VERSION 5.7 ;
  NAMESCASESENSITIVE ON ;
  NOWIREEXTENSIONATPIN ON ;
  DIVIDERCHAR "/" ;
  BUSBITCHARS "[]" ;
UNITS
  DATABASE MICRONS 200 ;
END UNITS

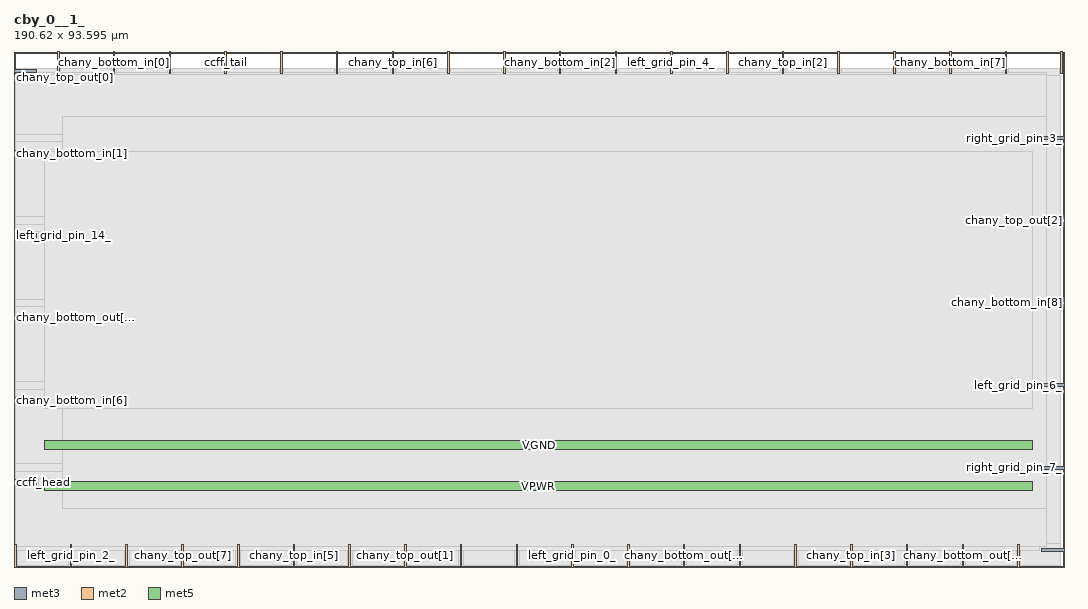
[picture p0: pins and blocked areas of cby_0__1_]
MACRO cby_0__1_
  CLASS BLOCK ;
  FOREIGN cby_0__1_ ;
  ORIGIN 0.000 0.000 ;
  SIZE 190.620 BY 93.595 ;
  PIN ccff_head
    DIRECTION INPUT ;
    PORT
      LAYER met3 ;
        RECT 0.000 15.000 4.000 15.600 ;
    END
  END ccff_head
  PIN ccff_tail
    DIRECTION OUTPUT TRISTATE ;
    PORT
      LAYER met2 ;
        RECT 38.270 89.595 38.550 93.595 ;
    END
  END ccff_tail
  PIN chany_bottom_in[0]
    DIRECTION INPUT ;
    PORT
      LAYER met2 ;
        RECT 18.030 89.595 18.310 93.595 ;
    END
  END chany_bottom_in[0]
  PIN chany_bottom_in[1]
    DIRECTION INPUT ;
    PORT
      LAYER met3 ;
        RECT 0.000 74.840 4.000 75.440 ;
    END
  END chany_bottom_in[1]
  PIN chany_bottom_in[2]
    DIRECTION INPUT ;
    PORT
      LAYER met2 ;
        RECT 98.990 89.595 99.270 93.595 ;
    END
  END chany_bottom_in[2]
  PIN chany_bottom_in[3]
    DIRECTION INPUT ;
    PORT
      LAYER met2 ;
        RECT 91.170 0.000 91.450 4.000 ;
    END
  END chany_bottom_in[3]
  PIN chany_bottom_in[4]
    DIRECTION INPUT ;
    PORT
      LAYER met2 ;
        RECT 111.410 0.000 111.690 4.000 ;
    END
  END chany_bottom_in[4]
  PIN chany_bottom_in[5]
    DIRECTION INPUT ;
    PORT
      LAYER met2 ;
        RECT 78.750 89.595 79.030 93.595 ;
    END
  END chany_bottom_in[5]
  PIN chany_bottom_in[6]
    DIRECTION INPUT ;
    PORT
      LAYER met3 ;
        RECT 0.000 29.960 4.000 30.560 ;
    END
  END chany_bottom_in[6]
  PIN chany_bottom_in[7]
    DIRECTION INPUT ;
    PORT
      LAYER met2 ;
        RECT 169.830 89.595 170.110 93.595 ;
    END
  END chany_bottom_in[7]
  PIN chany_bottom_in[8]
    DIRECTION INPUT ;
    PORT
      LAYER met3 ;
        RECT 186.620 47.640 190.620 48.240 ;
    END
  END chany_bottom_in[8]
  PIN chany_bottom_out[0]
    DIRECTION OUTPUT TRISTATE ;
    PORT
      LAYER met2 ;
        RECT 7.910 89.595 8.190 93.595 ;
    END
  END chany_bottom_out[0]
  PIN chany_bottom_out[1]
    DIRECTION OUTPUT TRISTATE ;
    PORT
      LAYER met2 ;
        RECT 121.530 0.000 121.810 4.000 ;
    END
  END chany_bottom_out[1]
  PIN chany_bottom_out[2]
    DIRECTION OUTPUT TRISTATE ;
    PORT
      LAYER met2 ;
        RECT 28.150 89.595 28.430 93.595 ;
    END
  END chany_bottom_out[2]
  PIN chany_bottom_out[3]
    DIRECTION OUTPUT TRISTATE ;
    PORT
      LAYER met2 ;
        RECT 109.110 89.595 109.390 93.595 ;
    END
  END chany_bottom_out[3]
  PIN chany_bottom_out[4]
    DIRECTION OUTPUT TRISTATE ;
    PORT
      LAYER met2 ;
        RECT 20.330 0.000 20.610 4.000 ;
    END
  END chany_bottom_out[4]
  PIN chany_bottom_out[5]
    DIRECTION OUTPUT TRISTATE ;
    PORT
      LAYER met2 ;
        RECT 172.130 0.000 172.410 4.000 ;
    END
  END chany_bottom_out[5]
  PIN chany_bottom_out[6]
    DIRECTION OUTPUT TRISTATE ;
    PORT
      LAYER met3 ;
        RECT 0.000 44.920 4.000 45.520 ;
    END
  END chany_bottom_out[6]
  PIN chany_bottom_out[7]
    DIRECTION OUTPUT TRISTATE ;
    PORT
      LAYER met3 ;
        RECT 186.620 2.760 190.620 3.360 ;
    END
  END chany_bottom_out[7]
  PIN chany_bottom_out[8]
    DIRECTION OUTPUT TRISTATE ;
    PORT
      LAYER met2 ;
        RECT 190.070 89.595 190.350 93.595 ;
    END
  END chany_bottom_out[8]
  PIN chany_top_in[0]
    DIRECTION INPUT ;
    PORT
      LAYER met2 ;
        RECT 162.010 0.000 162.290 4.000 ;
    END
  END chany_top_in[0]
  PIN chany_top_in[1]
    DIRECTION INPUT ;
    PORT
      LAYER met2 ;
        RECT 48.390 89.595 48.670 93.595 ;
    END
  END chany_top_in[1]
  PIN chany_top_in[2]
    DIRECTION INPUT ;
    PORT
      LAYER met2 ;
        RECT 139.470 89.595 139.750 93.595 ;
    END
  END chany_top_in[2]
  PIN chany_top_in[3]
    DIRECTION INPUT ;
    PORT
      LAYER met2 ;
        RECT 151.890 0.000 152.170 4.000 ;
    END
  END chany_top_in[3]
  PIN chany_top_in[4]
    DIRECTION INPUT ;
    PORT
      LAYER met2 ;
        RECT 88.870 89.595 89.150 93.595 ;
    END
  END chany_top_in[4]
  PIN chany_top_in[5]
    DIRECTION INPUT ;
    PORT
      LAYER met2 ;
        RECT 50.690 0.000 50.970 4.000 ;
    END
  END chany_top_in[5]
  PIN chany_top_in[6]
    DIRECTION INPUT ;
    PORT
      LAYER met2 ;
        RECT 68.630 89.595 68.910 93.595 ;
    END
  END chany_top_in[6]
  PIN chany_top_in[7]
    DIRECTION INPUT ;
    PORT
      LAYER met2 ;
        RECT 141.770 0.000 142.050 4.000 ;
    END
  END chany_top_in[7]
  PIN chany_top_in[8]
    DIRECTION INPUT ;
    PORT
      LAYER met2 ;
        RECT 159.710 89.595 159.990 93.595 ;
    END
  END chany_top_in[8]
  PIN chany_top_out[0]
    DIRECTION OUTPUT TRISTATE ;
    PORT
      LAYER met3 ;
        RECT 0.000 89.800 4.000 90.400 ;
    END
  END chany_top_out[0]
  PIN chany_top_out[1]
    DIRECTION OUTPUT TRISTATE ;
    PORT
      LAYER met2 ;
        RECT 70.930 0.000 71.210 4.000 ;
    END
  END chany_top_out[1]
  PIN chany_top_out[2]
    DIRECTION OUTPUT TRISTATE ;
    PORT
      LAYER met3 ;
        RECT 186.620 62.600 190.620 63.200 ;
    END
  END chany_top_out[2]
  PIN chany_top_out[3]
    DIRECTION OUTPUT TRISTATE ;
    PORT
      LAYER met2 ;
        RECT 149.590 89.595 149.870 93.595 ;
    END
  END chany_top_out[3]
  PIN chany_top_out[4]
    DIRECTION OUTPUT TRISTATE ;
    PORT
      LAYER met2 ;
        RECT 179.950 89.595 180.230 93.595 ;
    END
  END chany_top_out[4]
  PIN chany_top_out[5]
    DIRECTION OUTPUT TRISTATE ;
    PORT
      LAYER met2 ;
        RECT 182.250 0.000 182.530 4.000 ;
    END
  END chany_top_out[5]
  PIN chany_top_out[6]
    DIRECTION OUTPUT TRISTATE ;
    PORT
      LAYER met2 ;
        RECT 40.570 0.000 40.850 4.000 ;
    END
  END chany_top_out[6]
  PIN chany_top_out[7]
    DIRECTION OUTPUT TRISTATE ;
    PORT
      LAYER met2 ;
        RECT 30.450 0.000 30.730 4.000 ;
    END
  END chany_top_out[7]
  PIN chany_top_out[8]
    DIRECTION OUTPUT TRISTATE ;
    PORT
      LAYER met2 ;
        RECT 131.650 0.000 131.930 4.000 ;
    END
  END chany_top_out[8]
  PIN left_grid_pin_0_
    DIRECTION OUTPUT TRISTATE ;
    PORT
      LAYER met2 ;
        RECT 101.290 0.000 101.570 4.000 ;
    END
  END left_grid_pin_0_
  PIN left_grid_pin_10_
    DIRECTION OUTPUT TRISTATE ;
    PORT
      LAYER met2 ;
        RECT 81.050 0.000 81.330 4.000 ;
    END
  END left_grid_pin_10_
  PIN left_grid_pin_12_
    DIRECTION OUTPUT TRISTATE ;
    PORT
      LAYER met2 ;
        RECT 60.810 0.000 61.090 4.000 ;
    END
  END left_grid_pin_12_
  PIN left_grid_pin_14_
    DIRECTION OUTPUT TRISTATE ;
    PORT
      LAYER met3 ;
        RECT 0.000 59.880 4.000 60.480 ;
    END
  END left_grid_pin_14_
  PIN left_grid_pin_2_
    DIRECTION OUTPUT TRISTATE ;
    PORT
      LAYER met2 ;
        RECT 10.210 0.000 10.490 4.000 ;
    END
  END left_grid_pin_2_
  PIN left_grid_pin_4_
    DIRECTION OUTPUT TRISTATE ;
    PORT
      LAYER met2 ;
        RECT 119.230 89.595 119.510 93.595 ;
    END
  END left_grid_pin_4_
  PIN left_grid_pin_6_
    DIRECTION OUTPUT TRISTATE ;
    PORT
      LAYER met3 ;
        RECT 186.620 32.680 190.620 33.280 ;
    END
  END left_grid_pin_6_
  PIN left_grid_pin_8_
    DIRECTION OUTPUT TRISTATE ;
    PORT
      LAYER met2 ;
        RECT 0.090 0.000 0.370 4.000 ;
    END
  END left_grid_pin_8_
  PIN pReset
    DIRECTION INPUT ;
    PORT
      LAYER met2 ;
        RECT 58.510 89.595 58.790 93.595 ;
    END
  END pReset
  PIN prog_clk
    DIRECTION INPUT ;
    PORT
      LAYER met2 ;
        RECT 129.350 89.595 129.630 93.595 ;
    END
  END prog_clk
  PIN right_grid_pin_3_
    DIRECTION OUTPUT TRISTATE ;
    PORT
      LAYER met3 ;
        RECT 186.620 77.560 190.620 78.160 ;
    END
  END right_grid_pin_3_
  PIN right_grid_pin_7_
    DIRECTION OUTPUT TRISTATE ;
    PORT
      LAYER met3 ;
        RECT 186.620 17.720 190.620 18.320 ;
    END
  END right_grid_pin_7_
  PIN VPWR
    DIRECTION INPUT ;
    USE POWER ;
    PORT
      LAYER met5 ;
        RECT 5.520 13.840 184.920 15.440 ;
    END
  END VPWR
  PIN VGND
    DIRECTION INPUT ;
    USE GROUND ;
    PORT
      LAYER met5 ;
        RECT 5.520 21.340 184.920 22.940 ;
    END
  END VGND
  OBS
      LAYER li1 ;
        RECT 5.520 10.795 184.920 81.685 ;
      LAYER met1 ;
        RECT 0.530 0.380 188.990 90.400 ;
      LAYER met2 ;
        RECT 0.370 89.315 7.630 90.430 ;
        RECT 8.470 89.315 17.750 90.430 ;
        RECT 18.590 89.315 27.870 90.430 ;
        RECT 28.710 89.315 37.990 90.430 ;
        RECT 38.830 89.315 48.110 90.430 ;
        RECT 48.950 89.315 58.230 90.430 ;
        RECT 59.070 89.315 68.350 90.430 ;
        RECT 69.190 89.315 78.470 90.430 ;
        RECT 79.310 89.315 88.590 90.430 ;
        RECT 89.430 89.315 98.710 90.430 ;
        RECT 99.550 89.315 108.830 90.430 ;
        RECT 109.670 89.315 118.950 90.430 ;
        RECT 119.790 89.315 129.070 90.430 ;
        RECT 129.910 89.315 139.190 90.430 ;
        RECT 140.030 89.315 149.310 90.430 ;
        RECT 150.150 89.315 159.430 90.430 ;
        RECT 160.270 89.315 169.550 90.430 ;
        RECT 170.390 89.315 179.670 90.430 ;
        RECT 180.510 89.315 189.790 90.430 ;
        RECT 0.370 4.280 190.070 89.315 ;
        RECT 0.650 0.270 9.930 4.280 ;
        RECT 10.770 0.270 20.050 4.280 ;
        RECT 20.890 0.270 30.170 4.280 ;
        RECT 31.010 0.270 40.290 4.280 ;
        RECT 41.130 0.270 50.410 4.280 ;
        RECT 51.250 0.270 60.530 4.280 ;
        RECT 61.370 0.270 70.650 4.280 ;
        RECT 71.490 0.270 80.770 4.280 ;
        RECT 81.610 0.270 90.890 4.280 ;
        RECT 91.730 0.270 101.010 4.280 ;
        RECT 101.850 0.270 111.130 4.280 ;
        RECT 111.970 0.270 121.250 4.280 ;
        RECT 122.090 0.270 131.370 4.280 ;
        RECT 132.210 0.270 141.490 4.280 ;
        RECT 142.330 0.270 151.610 4.280 ;
        RECT 152.450 0.270 161.730 4.280 ;
        RECT 162.570 0.270 171.850 4.280 ;
        RECT 172.690 0.270 181.970 4.280 ;
        RECT 182.810 0.270 190.070 4.280 ;
      LAYER met3 ;
        RECT 4.400 89.400 187.410 89.800 ;
        RECT 0.310 78.560 187.410 89.400 ;
        RECT 0.310 77.160 186.220 78.560 ;
        RECT 0.310 75.840 187.410 77.160 ;
        RECT 4.400 74.440 187.410 75.840 ;
        RECT 0.310 63.600 187.410 74.440 ;
        RECT 0.310 62.200 186.220 63.600 ;
        RECT 0.310 60.880 187.410 62.200 ;
        RECT 4.400 59.480 187.410 60.880 ;
        RECT 0.310 48.640 187.410 59.480 ;
        RECT 0.310 47.240 186.220 48.640 ;
        RECT 0.310 45.920 187.410 47.240 ;
        RECT 4.400 44.520 187.410 45.920 ;
        RECT 0.310 33.680 187.410 44.520 ;
        RECT 0.310 32.280 186.220 33.680 ;
        RECT 0.310 30.960 187.410 32.280 ;
        RECT 4.400 29.560 187.410 30.960 ;
        RECT 0.310 18.720 187.410 29.560 ;
        RECT 0.310 17.320 186.220 18.720 ;
        RECT 0.310 16.000 187.410 17.320 ;
        RECT 4.400 14.600 187.410 16.000 ;
        RECT 0.310 3.760 187.410 14.600 ;
        RECT 0.310 2.910 186.220 3.760 ;
      LAYER met4 ;
        RECT 8.720 10.640 187.385 81.840 ;
      LAYER met5 ;
        RECT 5.520 28.840 184.920 75.440 ;
  END
END cby_0__1_
END LIBRARY

